VERSION 5.7 ;
  NOWIREEXTENSIONATPIN ON ;
  DIVIDERCHAR "/" ;
  BUSBITCHARS "[]" ;
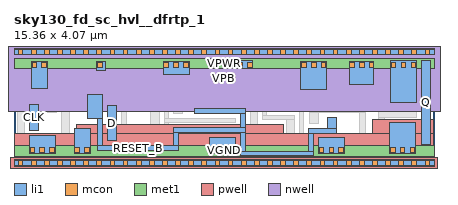
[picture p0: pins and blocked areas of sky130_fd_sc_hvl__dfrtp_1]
MACRO sky130_fd_sc_hvl__dfrtp_1
  CLASS BLOCK ;
  FOREIGN sky130_fd_sc_hvl__dfrtp_1 ;
  ORIGIN 0.000 0.000 ;
  SIZE 15.360 BY 4.070 ;
  PIN CLK
    ANTENNAGATEAREA 0.585000 ;
    PORT
      LAYER li1 ;
        RECT 0.560 1.175 0.890 2.150 ;
    END
  END CLK
  PIN D
    ANTENNAGATEAREA 0.420000 ;
    PORT
      LAYER li1 ;
        RECT 3.415 0.810 3.745 2.105 ;
    END
  END D
  PIN RESET_B
    ANTENNAGATEAREA 1.260000 ;
    PORT
      LAYER li1 ;
        RECT 2.695 1.620 3.235 2.490 ;
        RECT 6.605 1.825 8.460 1.995 ;
        RECT 3.065 0.630 3.235 1.620 ;
        RECT 8.290 1.295 8.460 1.825 ;
        RECT 5.840 1.125 8.460 1.295 ;
        RECT 11.455 1.265 11.785 1.655 ;
        RECT 5.840 0.630 6.010 1.125 ;
        RECT 3.065 0.460 6.010 0.630 ;
        RECT 8.290 0.435 8.460 1.125 ;
        RECT 10.780 1.095 11.785 1.265 ;
        RECT 10.780 0.435 10.950 1.095 ;
        RECT 8.290 0.265 10.950 0.435 ;
    END
  END RESET_B
  PIN VGND
    USE GROUND ;
    PORT
      LAYER li1 ;
        RECT 0.560 0.365 1.510 0.995 ;
        RECT 2.200 0.365 2.790 1.245 ;
        RECT 7.160 0.365 8.110 0.945 ;
        RECT 11.130 0.365 12.080 0.915 ;
        RECT 13.735 0.365 14.685 1.495 ;
      LAYER mcon ;
        RECT 0.590 0.395 0.760 0.565 ;
        RECT 0.950 0.395 1.120 0.565 ;
        RECT 1.310 0.395 1.480 0.565 ;
        RECT 2.230 0.395 2.400 0.565 ;
        RECT 2.590 0.395 2.760 0.565 ;
        RECT 7.190 0.395 7.360 0.565 ;
        RECT 7.550 0.395 7.720 0.565 ;
        RECT 7.910 0.395 8.080 0.565 ;
        RECT 11.160 0.395 11.330 0.565 ;
        RECT 11.520 0.395 11.690 0.565 ;
        RECT 11.880 0.395 12.050 0.565 ;
        RECT 13.765 0.395 13.935 0.565 ;
        RECT 14.125 0.395 14.295 0.565 ;
        RECT 14.485 0.395 14.655 0.565 ;
      LAYER met1 ;
        RECT 0.000 0.255 15.360 0.625 ;
    END
  END VGND
  PIN VNB
    ANTENNADIFFAREA 2.611200 ;
    PORT
      LAYER pwell ;
        RECT 2.270 1.085 9.870 1.415 ;
        RECT 13.115 1.085 15.340 1.585 ;
        RECT 0.020 0.215 15.340 1.085 ;
        RECT -0.130 -0.215 15.490 0.215 ;
      LAYER li1 ;
        RECT 0.000 -0.085 15.360 0.085 ;
      LAYER mcon ;
        RECT 0.155 -0.085 0.325 0.085 ;
        RECT 0.635 -0.085 0.805 0.085 ;
        RECT 1.115 -0.085 1.285 0.085 ;
        RECT 1.595 -0.085 1.765 0.085 ;
        RECT 2.075 -0.085 2.245 0.085 ;
        RECT 2.555 -0.085 2.725 0.085 ;
        RECT 3.035 -0.085 3.205 0.085 ;
        RECT 3.515 -0.085 3.685 0.085 ;
        RECT 3.995 -0.085 4.165 0.085 ;
        RECT 4.475 -0.085 4.645 0.085 ;
        RECT 4.955 -0.085 5.125 0.085 ;
        RECT 5.435 -0.085 5.605 0.085 ;
        RECT 5.915 -0.085 6.085 0.085 ;
        RECT 6.395 -0.085 6.565 0.085 ;
        RECT 6.875 -0.085 7.045 0.085 ;
        RECT 7.355 -0.085 7.525 0.085 ;
        RECT 7.835 -0.085 8.005 0.085 ;
        RECT 8.315 -0.085 8.485 0.085 ;
        RECT 8.795 -0.085 8.965 0.085 ;
        RECT 9.275 -0.085 9.445 0.085 ;
        RECT 9.755 -0.085 9.925 0.085 ;
        RECT 10.235 -0.085 10.405 0.085 ;
        RECT 10.715 -0.085 10.885 0.085 ;
        RECT 11.195 -0.085 11.365 0.085 ;
        RECT 11.675 -0.085 11.845 0.085 ;
        RECT 12.155 -0.085 12.325 0.085 ;
        RECT 12.635 -0.085 12.805 0.085 ;
        RECT 13.115 -0.085 13.285 0.085 ;
        RECT 13.595 -0.085 13.765 0.085 ;
        RECT 14.075 -0.085 14.245 0.085 ;
        RECT 14.555 -0.085 14.725 0.085 ;
        RECT 15.035 -0.085 15.205 0.085 ;
      LAYER met1 ;
        RECT 0.000 -0.115 15.360 0.115 ;
    END
  END VNB
  PIN VPB
    ANTENNADIFFAREA 2.611200 ;
    PORT
      LAYER nwell ;
        RECT -0.330 1.885 15.690 4.485 ;
      LAYER li1 ;
        RECT 0.000 3.985 15.360 4.155 ;
      LAYER mcon ;
        RECT 0.155 3.985 0.325 4.155 ;
        RECT 0.635 3.985 0.805 4.155 ;
        RECT 1.115 3.985 1.285 4.155 ;
        RECT 1.595 3.985 1.765 4.155 ;
        RECT 2.075 3.985 2.245 4.155 ;
        RECT 2.555 3.985 2.725 4.155 ;
        RECT 3.035 3.985 3.205 4.155 ;
        RECT 3.515 3.985 3.685 4.155 ;
        RECT 3.995 3.985 4.165 4.155 ;
        RECT 4.475 3.985 4.645 4.155 ;
        RECT 4.955 3.985 5.125 4.155 ;
        RECT 5.435 3.985 5.605 4.155 ;
        RECT 5.915 3.985 6.085 4.155 ;
        RECT 6.395 3.985 6.565 4.155 ;
        RECT 6.875 3.985 7.045 4.155 ;
        RECT 7.355 3.985 7.525 4.155 ;
        RECT 7.835 3.985 8.005 4.155 ;
        RECT 8.315 3.985 8.485 4.155 ;
        RECT 8.795 3.985 8.965 4.155 ;
        RECT 9.275 3.985 9.445 4.155 ;
        RECT 9.755 3.985 9.925 4.155 ;
        RECT 10.235 3.985 10.405 4.155 ;
        RECT 10.715 3.985 10.885 4.155 ;
        RECT 11.195 3.985 11.365 4.155 ;
        RECT 11.675 3.985 11.845 4.155 ;
        RECT 12.155 3.985 12.325 4.155 ;
        RECT 12.635 3.985 12.805 4.155 ;
        RECT 13.115 3.985 13.285 4.155 ;
        RECT 13.595 3.985 13.765 4.155 ;
        RECT 14.075 3.985 14.245 4.155 ;
        RECT 14.555 3.985 14.725 4.155 ;
        RECT 15.035 3.985 15.205 4.155 ;
      LAYER met1 ;
        RECT 0.000 3.955 15.360 4.185 ;
    END
  END VPB
  PIN VPWR
    USE POWER ;
    PORT
      LAYER li1 ;
        RECT 0.630 2.725 1.220 3.705 ;
        RECT 3.020 3.370 3.350 3.705 ;
        RECT 5.450 3.225 6.400 3.705 ;
        RECT 7.790 3.455 8.740 3.755 ;
        RECT 10.485 2.675 11.435 3.705 ;
        RECT 12.270 2.885 13.165 3.705 ;
        RECT 13.775 2.195 14.720 3.735 ;
      LAYER mcon ;
        RECT 0.660 3.505 0.830 3.675 ;
        RECT 1.020 3.505 1.190 3.675 ;
        RECT 3.050 3.505 3.220 3.675 ;
        RECT 5.480 3.505 5.650 3.675 ;
        RECT 5.840 3.505 6.010 3.675 ;
        RECT 6.200 3.505 6.370 3.675 ;
        RECT 7.820 3.505 7.990 3.675 ;
        RECT 8.180 3.505 8.350 3.675 ;
        RECT 8.540 3.505 8.710 3.675 ;
        RECT 10.515 3.505 10.685 3.675 ;
        RECT 10.875 3.505 11.045 3.675 ;
        RECT 11.235 3.505 11.405 3.675 ;
        RECT 12.270 3.505 12.440 3.675 ;
        RECT 12.630 3.505 12.800 3.675 ;
        RECT 12.990 3.505 13.160 3.675 ;
        RECT 13.800 3.505 13.970 3.675 ;
        RECT 14.160 3.505 14.330 3.675 ;
        RECT 14.520 3.505 14.690 3.675 ;
      LAYER met1 ;
        RECT 0.000 3.445 15.360 3.815 ;
    END
  END VPWR
  PIN Q
    ANTENNADIFFAREA 0.611250 ;
    PORT
      LAYER li1 ;
        RECT 14.900 0.665 15.235 3.735 ;
    END
  END Q
  OBS
      LAYER li1 ;
        RECT 1.400 3.635 2.840 3.805 ;
        RECT 0.110 2.525 0.440 3.455 ;
        RECT 1.400 2.525 1.570 3.635 ;
        RECT 0.110 2.355 1.570 2.525 ;
        RECT 0.110 0.495 0.380 2.355 ;
        RECT 1.240 1.855 1.570 2.355 ;
        RECT 1.750 2.150 2.000 3.455 ;
        RECT 2.240 2.840 2.490 3.455 ;
        RECT 2.670 3.190 2.840 3.635 ;
        RECT 3.530 3.635 5.270 3.805 ;
        RECT 3.530 3.190 3.700 3.635 ;
        RECT 2.670 3.020 3.700 3.190 ;
        RECT 3.880 2.840 4.050 3.455 ;
        RECT 4.580 3.200 4.910 3.455 ;
        RECT 2.240 2.670 4.050 2.840 ;
        RECT 4.230 2.670 4.450 3.000 ;
        RECT 3.880 2.490 4.050 2.670 ;
        RECT 3.880 2.320 4.100 2.490 ;
        RECT 1.750 1.920 2.275 2.150 ;
        RECT 1.750 0.995 2.020 1.920 ;
        RECT 1.690 0.495 2.020 0.995 ;
        RECT 3.930 1.325 4.100 2.320 ;
        RECT 4.280 2.150 4.450 2.670 ;
        RECT 4.630 2.500 4.800 3.200 ;
        RECT 5.100 3.045 5.270 3.635 ;
        RECT 6.580 3.635 7.610 3.805 ;
        RECT 6.580 3.045 6.750 3.635 ;
        RECT 5.100 3.000 6.750 3.045 ;
        RECT 4.980 2.875 6.750 3.000 ;
        RECT 4.980 2.680 5.310 2.875 ;
        RECT 6.930 2.695 7.260 3.455 ;
        RECT 7.440 3.275 7.610 3.635 ;
        RECT 7.440 3.105 9.250 3.275 ;
        RECT 5.490 2.525 7.260 2.695 ;
        RECT 5.490 2.500 5.660 2.525 ;
        RECT 4.630 2.330 5.660 2.500 ;
        RECT 8.570 2.345 8.900 2.925 ;
        RECT 4.280 1.920 5.305 2.150 ;
        RECT 4.975 1.425 5.305 1.920 ;
        RECT 5.490 1.645 5.660 2.330 ;
        RECT 5.840 2.175 8.900 2.345 ;
        RECT 5.840 1.825 6.170 2.175 ;
        RECT 5.490 1.475 8.110 1.645 ;
        RECT 3.930 0.825 4.200 1.325 ;
        RECT 5.490 1.245 5.660 1.475 ;
        RECT 4.650 1.075 5.660 1.245 ;
        RECT 8.640 1.325 8.900 2.175 ;
        RECT 9.080 1.755 9.250 3.105 ;
        RECT 9.430 2.845 9.680 3.755 ;
        RECT 9.430 2.675 10.305 2.845 ;
        RECT 9.625 1.935 9.955 2.435 ;
        RECT 10.135 2.355 10.305 2.675 ;
        RECT 11.840 2.705 12.090 3.175 ;
        RECT 11.840 2.535 12.845 2.705 ;
        RECT 10.135 2.185 12.495 2.355 ;
        RECT 9.080 1.585 10.250 1.755 ;
        RECT 4.650 0.825 4.980 1.075 ;
        RECT 8.640 0.615 8.970 1.325 ;
        RECT 9.430 0.785 9.760 1.325 ;
        RECT 9.965 1.085 10.250 1.585 ;
        RECT 10.430 0.785 10.600 2.185 ;
        RECT 12.675 2.005 12.845 2.535 ;
        RECT 10.805 1.835 12.845 2.005 ;
        RECT 10.805 1.445 11.135 1.835 ;
        RECT 9.430 0.615 10.600 0.785 ;
        RECT 12.620 0.995 12.845 1.835 ;
        RECT 13.345 2.005 13.595 3.005 ;
        RECT 13.345 1.675 14.720 2.005 ;
        RECT 13.345 1.495 13.555 1.675 ;
        RECT 13.225 0.995 13.555 1.495 ;
        RECT 12.620 0.495 12.950 0.995 ;
      LAYER mcon ;
        RECT 2.075 1.950 2.245 2.120 ;
        RECT 4.475 1.950 4.645 2.120 ;
        RECT 9.755 1.950 9.925 2.120 ;
      LAYER met1 ;
        RECT 2.015 2.105 2.305 2.150 ;
        RECT 4.415 2.105 4.705 2.150 ;
        RECT 9.695 2.105 9.985 2.150 ;
        RECT 2.015 1.965 9.985 2.105 ;
        RECT 2.015 1.920 2.305 1.965 ;
        RECT 4.415 1.920 4.705 1.965 ;
        RECT 9.695 1.920 9.985 1.965 ;
  END
END sky130_fd_sc_hvl__dfrtp_1
END LIBRARY

